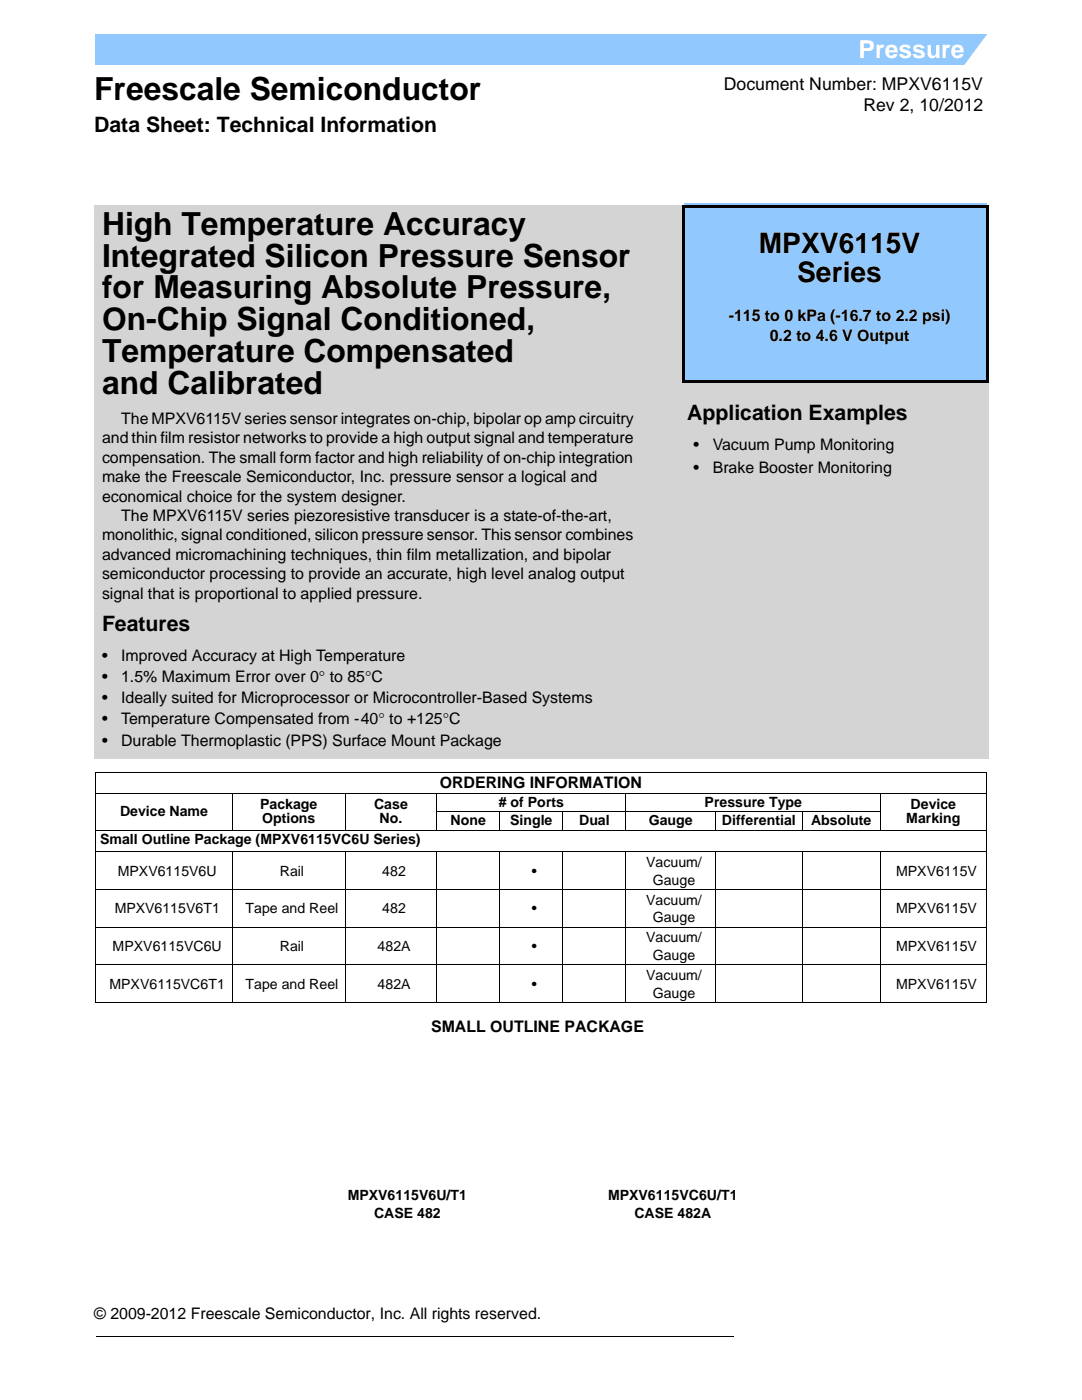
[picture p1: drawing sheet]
<svg xmlns="http://www.w3.org/2000/svg" width="216mm" height="279mm" viewBox="0 0 216 279" stroke-linecap="round" stroke-linejoin="round" font-family="sans-serif">
<defs><g id="words">
<g font-size="6.3">
<text x="18.8" y="19.9">Freescale Semiconductor</text>
<text x="20.4" y="46.8">High Temperature Accuracy</text>
<text x="20.4" y="53.2">Integrated Silicon Pressure Sensor</text>
<text x="20.4" y="59.5">for Measuring Absolute Pressure,</text>
<text x="20.4" y="65.9">On-Chip Signal Conditioned,</text>
<text x="20.4" y="72.2">Temperature Compensated</text>
<text x="20.4" y="78.6">and Calibrated</text>
</g>
<g font-size="5.6">
<text x="151.4" y="50.5">MPXV6115V</text>
<text x="159.1" y="56.3">Series</text>
</g>
<text font-size="4.9" fill="#fff" x="171.3" y="11.7">Pressure</text>
<g font-size="4.2">
<text x="18.8" y="26.3">Data Sheet: Technical Information</text>
<text x="137.1" y="83.9">Application Examples</text>
<text x="20.4" y="125.9">Features</text>
</g>
<g font-size="3.5">
<text x="144.4" y="18">Document Number: MPXV6115V</text>
<text x="172.3" y="22.2">Rev 2, 10/2012</text>
</g>
<g font-size="3.2">
<text x="145.4" y="64.2">-115 to 0 kPa (-16.7 to 2.2 psi)</text>
<text x="153.6" y="68.1">0.2 to 4.6 V Output</text>
<text x="20.4" y="88.5">and thin film resistor networks to provide a high output signal and temperature</text>
<text x="24.2" y="84.6">The MPXV6115V series sensor integrates on-chip, bipolar op amp circuitry</text>
<text x="138.4" y="89.9">•</text>
<text x="142.2" y="89.9">Vacuum Pump Monitoring</text>
<text x="20.4" y="92.4">compensation. The small form factor and high reliability of on-chip integration</text>
<text x="138.4" y="94.5">•</text>
<text x="142.2" y="94.5">Brake Booster Monitoring</text>
<text x="20.4" y="96.2">make the Freescale Semiconductor, Inc. pressure sensor a logical and</text>
<text x="20.4" y="100.1">economical choice for the system designer.</text>
<text x="20.4" y="107.9">monolithic, signal conditioned, silicon pressure sensor. This sensor combines</text>
<text x="24.2" y="104">The MPXV6115V series piezoresistive transducer is a state-of-the-art,</text>
<text x="20.4" y="111.8">advanced micromachining techniques, thin film metallization, and bipolar</text>
<text x="20.4" y="115.6">semiconductor processing to provide an accurate, high level analog output</text>
<text x="20.4" y="119.5">signal that is proportional to applied pressure.</text>
<text x="20.4" y="131.9">•</text>
<text x="24.2" y="131.9">Improved Accuracy at High Temperature</text>
<text x="20.4" y="136.1">•</text>
<text x="24.2" y="136.1">1.5% Maximum Error over 0° to 85°C</text>
<text x="20.4" y="140.3">•</text>
<text x="24.2" y="140.3">Ideally suited for Microprocessor or Microcontroller-Based Systems</text>
<text x="20.4" y="148.8">•</text>
<text x="20.4" y="144.6">•</text>
<text x="24.2" y="148.8">Durable Thermoplastic (PPS) Surface Mount Package</text>
<text x="24.2" y="144.6">Temperature Compensated from -40° to +125°C</text>
<text x="87.8" y="157.3">ORDERING INFORMATION</text>
<text x="86" y="206">SMALL OUTLINE PACKAGE</text>
<text x="18.8" y="263.2">© 2009-2012 Freescale Semiconductor, Inc. All rights reserved.</text>
</g>
<g font-size="2.8">
<text x="51.9" y="161.5">Package</text>
<text x="74.6" y="161.5">Case</text>
<text x="99.5" y="161.1"># of Ports</text>
<text x="140.6" y="161.1">Pressure Type</text>
<text x="181.7" y="161.5">Device</text>
<text x="24" y="162.9">Device Name</text>
<text x="52.3" y="164.3">Options</text>
<text x="75.7" y="164.3">No.</text>
<text x="89.9" y="164.7">None</text>
<text x="101.8" y="164.7">Single</text>
<text x="115.5" y="164.7">Dual</text>
<text x="129.5" y="164.7">Gauge</text>
<text x="144" y="164.7">Differential</text>
<text x="161.8" y="164.7">Absolute</text>
<text x="180.8" y="164.3">Marking</text>
<text x="20" y="168.3">Small Outline Package (MPXV6115VC6U Series)</text>
<text x="128.9" y="173">Vacuum/</text>
<text x="23.5" y="174.8">MPXV6115V6U</text>
<text x="55.8" y="174.8">Rail</text>
<text x="76.3" y="174.8">482</text>
<text x="106.2" y="174.8">•</text>
<text x="130.3" y="176.6">Gauge</text>
<text x="178.8" y="174.8">MPXV6115V</text>
<text x="22.9" y="182.3">MPXV6115V6T1</text>
<text x="49" y="182.3">Tape and Reel</text>
<text x="76.3" y="182.3">482</text>
<text x="106.2" y="182.3">•</text>
<text x="128.9" y="180.6">Vacuum/</text>
<text x="130.3" y="184.1">Gauge</text>
<text x="178.8" y="182.3">MPXV6115V</text>
<text x="22.5" y="189.8">MPXV6115VC6U</text>
<text x="55.8" y="189.8">Rail</text>
<text x="75.4" y="189.8">482A</text>
<text x="106.2" y="189.8">•</text>
<text x="128.9" y="188.1">Vacuum/</text>
<text x="130.3" y="191.6">Gauge</text>
<text x="178.8" y="189.8">MPXV6115V</text>
<text x="21.8" y="197.3">MPXV6115VC6T1</text>
<text x="49" y="197.3">Tape and Reel</text>
<text x="75.4" y="197.3">482A</text>
<text x="106.2" y="197.3">•</text>
<text x="128.9" y="195.6">Vacuum/</text>
<text x="178.8" y="197.3">MPXV6115V</text>
<text x="130.3" y="199.1">Gauge</text>
<text x="69.4" y="239.5">MPXV6115V6U/T1</text>
<text x="121.3" y="239.5">MPXV6115VC6U/T1</text>
<text x="74.6" y="243">CASE 482</text>
<text x="126.6" y="243.1">CASE 482A</text>
</g>
</g></defs>
<path d="M146.3 266.6l.1 .1z" fill="#000"/>
<path d="M19.2 266.6h127.1" fill="none" stroke="#000" stroke-width=".2"/>
<path d="M19 6.9h177.8v6h-177.8z" fill="#91c9ff"/>
<path d="M197.3 6.4h1.5v7.1h-6.8z" fill="#fff"/>
<path d="M152.4 254.6h44v12.8h-44z" fill="#fff"/>
<path d="M134.9 82.9h61.3v41.7h-61.3z" fill="#d4d4d4"/>
<path d="M134.9 82.9h61.3M134.9 82.8v41.8M196.2 82.9v41.8M134.9 124.6h61.3" fill="none" stroke="#d4d4d4" stroke-width=".2"/>
<path d="M18.9 41h178.3v110.3h-178.3z" fill="#d4d4d4"/>
<path d="M18.9 40.9v110.4M18.9 41h178.4M197.2 41v110.4M18.9 151.3h178.3" fill="none" stroke="#d4d4d4" stroke-width=".2"/>
<g fill="#fff">
<path d="M19.1 154.1h177.7v4.3h-177.7z"/>
<path d="M19.1 165.7h177.7v4.3h-177.7z"/>
<path d="M19.1 170h27.3v7.5h-27.3z"/>
<path d="M46.4 170h22.5v7.5h-22.5z"/>
<path d="M68.9 170h18.3v7.5h-18.3z"/>
<path d="M87.2 170h25.1v7.5h-25.1z"/>
<path d="M112.3 170h30.5v7.5h-30.5z"/>
<path d="M142.8 170h54v7.5h-54z"/>
<path d="M19.1 177.5h27.3v7.6h-27.3z"/>
<path d="M46.4 177.5h22.5v7.6h-22.5z"/>
<path d="M68.9 177.5h18.3v7.6h-18.3z"/>
<path d="M87.2 177.5h25.1v7.6h-25.1z"/>
<path d="M112.3 177.5h30.5v7.6h-30.5z"/>
<path d="M142.8 177.5h54v7.6h-54z"/>
<path d="M19.1 185.1h27.3v7.5h-27.3z"/>
<path d="M46.4 185.1h22.5v7.5h-22.5z"/>
<path d="M68.9 185.1h18.3v7.5h-18.3z"/>
<path d="M87.2 185.1h25.1v7.5h-25.1z"/>
<path d="M112.3 185.1h30.5v7.5h-30.5z"/>
<path d="M142.8 185.1h54v7.5h-54z"/>
<path d="M19.1 192.6h27.3v7.5h-27.3z"/>
<path d="M46.4 192.6h22.5v7.5h-22.5z"/>
<path d="M68.9 192.6h18.3v7.5h-18.3z"/>
<path d="M87.2 192.6h25.1v7.5h-25.1z"/>
<path d="M112.3 192.6h30.5v7.5h-30.5z"/>
<path d="M142.8 192.6h54v7.5h-54z"/>
</g>
<g fill="none" stroke="#000" stroke-width=".2">
<path d="M19 154.1h177.9M19 158.4h177.9M19.1 154.2v45.8M46.4 158.3v7.5M68.9 158.3v7.5M87.2 158.3v7.5M124.9 158.3v7.5M175.7 158.3v7.5M196.8 154.2v45.8M19 165.7h177.9M19 170h177.9M19 177.5h177.9"/>
<path d="M46.4 169.9v30.3M68.9 169.9v30.3M87.1 162.1h88.7M87.2 169.9v30.3M99.7 162v3.8M99.7 169.9v30.3M112.3 162v3.8M112.3 169.9v30.3M124.9 169.9v30.3M142.8 162v3.8M142.8 169.9v30.3M160 162v3.8"/>
<path d="M160 169.9v30.3M175.7 169.9v30.3M19 185.1h177.9M19 192.6h177.9M19 200.1h177.9"/>
</g>
<g fill="#fff">
<path d="M68.6 213.4h28v20h-28z"/>
<path d="M120.1 211.5h28.6v23.7h-28.6z"/>
</g>
<path d="M136.6 40.7h60.3v35.1h-60.3z" fill="#91c9ff"/>
<path d="M136.6 40.7h60.4M136.6 40.6v35.2M196.9 40.7v35.2M136.5 75.8h60.4" fill="none" stroke="#91c9ff" stroke-width=".2"/>
<path d="M136.3 40.9h61v.5h-61zM136.1 75.9h60.9v.5h-60.9zM136.1 40.9h.5v35.3h-.5zM196.8 41.1h.5v35.3h-.5z" fill="#000"/>
<use href="#words"/>
</svg>
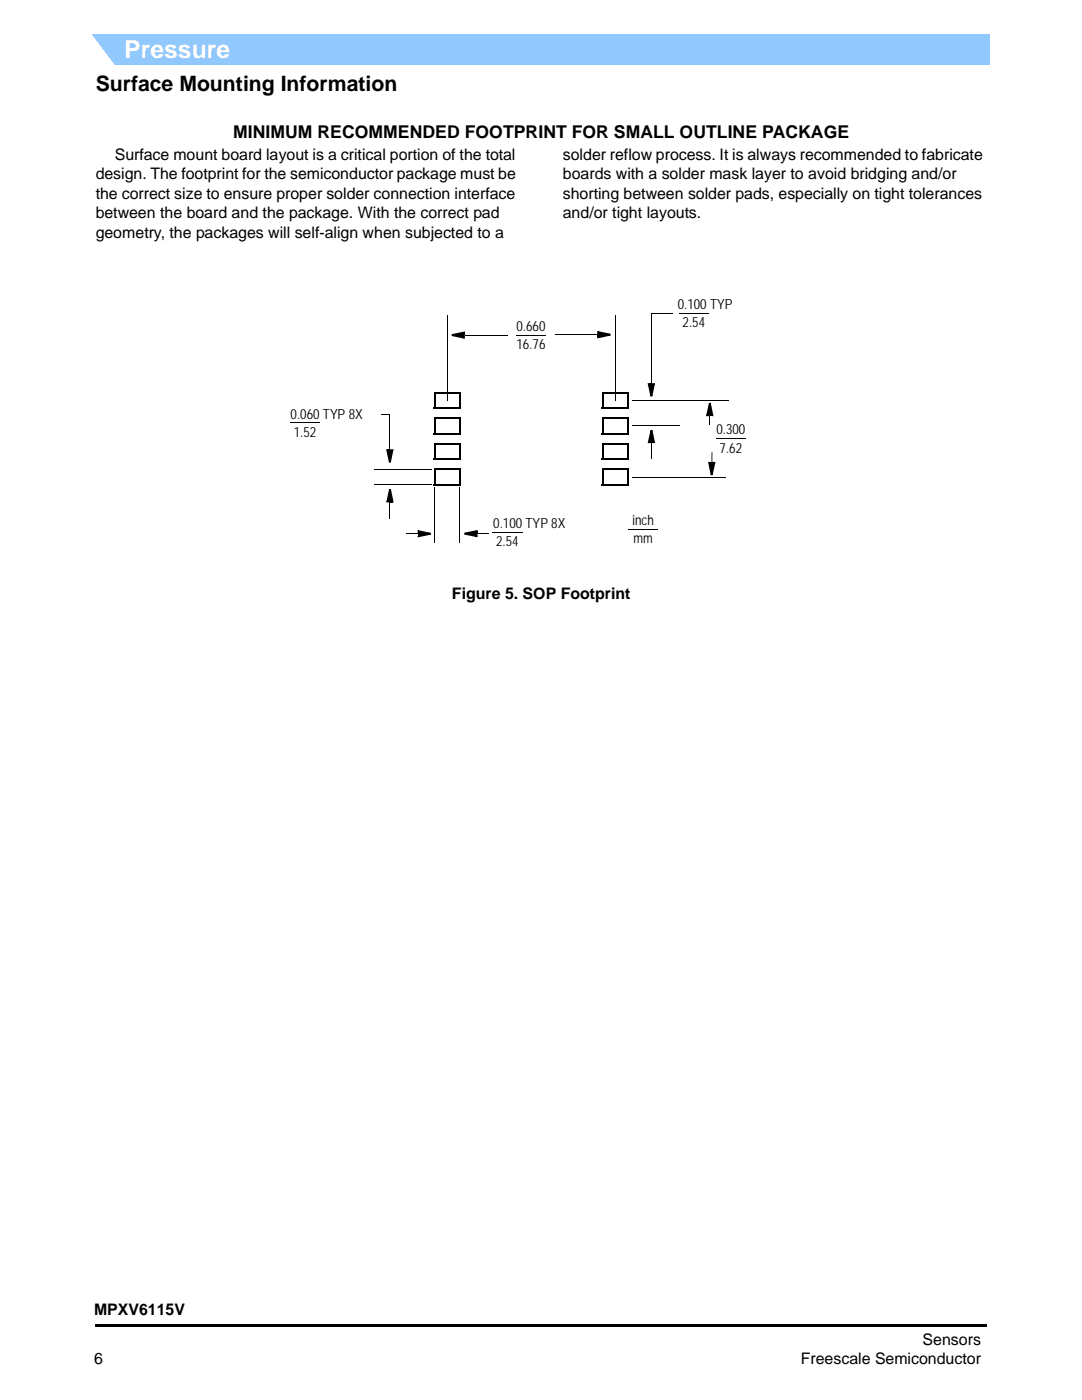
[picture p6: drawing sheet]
<svg xmlns="http://www.w3.org/2000/svg" width="216mm" height="279mm" viewBox="0 0 216 279" stroke-linecap="round" stroke-linejoin="round" font-family="sans-serif">
<defs><g id="words">
<text font-size="4.9" fill="#fff" x="24.8" y="11.7">Pressure</text>
<text font-size="4.2" x="19.1" y="18.2">Surface Mounting Information</text>
<text font-size="3.5" x="46.5" y="27.6">MINIMUM RECOMMENDED FOOTPRINT FOR SMALL OUTLINE PACKAGE</text>
<g font-size="3.2">
<text x="19.1" y="35.8">design. The footprint for the semiconductor package must be</text>
<text x="22.9" y="31.9">Surface mount board layout is a critical portion of the total</text>
<text x="112.3" y="31.9">solder reflow process. It is always recommended to fabricate</text>
<text x="112.3" y="35.8">boards with a solder mask layer to avoid bridging and/or</text>
<text x="19.1" y="39.7">the correct size to ensure proper solder connection interface</text>
<text x="112.3" y="39.7">shorting between solder pads, especially on tight tolerances</text>
<text x="19.1" y="43.6">between the board and the package. With the correct pad</text>
<text x="19.1" y="47.4">geometry, the packages will self-align when subjected to a</text>
<text x="112.3" y="43.6">and/or tight layouts.</text>
<text x="90.2" y="119.5">Figure 5. SOP Footprint</text>
<text x="18.8" y="262.4">MPXV6115V</text>
<text x="184.1" y="268.4">Sensors</text>
<text x="18.8" y="272.3">6</text>
<text x="159.8" y="272.3">Freescale Semiconductor</text>
</g>
<g font-size="2.8">
<text x="135.3" y="61.7">0.100 TYP</text>
<text x="136.2" y="65.3">2.54</text>
<text x="103.1" y="66">0.660</text>
<text x="103.1" y="69.7">16.76</text>
<text x="58" y="83.5">0.060 TYP 8X</text>
<text x="58.6" y="87.1">1.52</text>
<text x="142.9" y="86.7">0.300</text>
<text x="143.6" y="90.3">7.62</text>
<text x="98.4" y="105.4">0.100 TYP 8X</text>
<text x="126.2" y="104.7">inch</text>
<text x="99" y="109.1">2.54</text>
<text x="126.4" y="108.4">mm</text>
</g>
</g></defs>
<path d="M19 264.3h177.7v.6h-177.7zM196.7 264.3h.2v.6h-.2z" fill="#000"/>
<path d="M18.4 6.9h179.2v6h-179.2z" fill="#91c9ff"/>
<path d="M16.5 6.4h1.4l5.4 7.1h-6.8z" fill="#fff"/>
<path d="M21.9 52h172.2v64.7h-172.2z" fill="#fff"/>
<g fill="#000">
<path d="M86.6 78.3h.1v.2h-.1zM89.2 63l.1 .1zM91.7 78.3h.2v.1h-.2zM92.4 66.4h.4v.5h-.4zM90.1 66.7l2.7-.6-.2 .4-2.4 .6v-.4l2.4 .5-.1 .4-.1-.2v-.5h.4v.7l-2.7-.5zM103 66.8l.1 .2zM119.2 66.8h.3v.5h-.3zM119.2 66.1l2.6 .5v.4l-2.6 .5 .1-.4 2.4-.5 .1 .4-2.5-.5 .1-.4 .1 .2v.5h-.3zM120.1 78.3h.1v.2h-.1zM122.7 63l.2 .1zM125.2 78.3h.3v.1h-.3zM129.5 76.5h.5v.3h-.5z"/>
<path d="M129.9 62.5l.1 .2zM129.2 76.5l.4 .1 .6 2.4-.4 .1 .5-2.5 .4 .1-.2 .1h-.5v-.3h.7l-.5 2.6h-.4zM135.5 62.5l.1 .1zM57.8 84.3l.1 .1zM74.6 93.6l.1 .1zM74.6 96.6l.1 .2zM76.1 82.5v.2zM76.1 82.5h1.8v.2h-1.8zM77.3 89.7h.5v.3h-.5zM77 89.7l.4 .1 .6 2.4h-.4l.5-2.4 .4 .1-.2 .1h-.5v-.3h.7l-.5 2.6h-.4zM86.6 93.5h.1v.3h-.1zM86.6 96.7h.2v.1h-.2z"/>
<path d="M86.6 88.4h.1v.3h-.1zM86.6 91.6h.2v.1h-.2zM86.6 83.4h.1v.2h-.1zM86.6 86.5h.2v.2h-.2zM86.6 81.4h.2v.2h-.2zM86.6 97.3l.2 .1zM91.7 93.5h.2v.1h-.2zM91.7 88.4h.2v.2h-.2zM91.7 83.4h.2v.1h-.2zM91.7 97.3l.2 .1zM91.8 96.6h.1v.2h-.1zM91.8 91.5h.1v.3h-.1z"/>
<path d="M91.8 86.4h.1v.3h-.1zM91.8 81.3h.1v.3h-.1zM120.1 93.5h.1v.3h-.1zM120.1 96.7h.3v.1h-.3zM120.1 88.4h.1v.3h-.1zM120.1 91.6h.3v.1h-.3zM120.1 83.4h.1v.2h-.1zM120.1 86.5h.3v.2h-.3zM120.1 81.4h.3v.2h-.3zM125.2 93.5h.3v.1h-.3zM125.2 88.4h.3v.2h-.3zM125.2 83.4h.3v.1h-.3z"/>
<path d="M125.3 96.6h.1v.2h-.1zM125.3 91.5h.1v.3h-.1zM125.3 86.4h.1v.3h-.1zM125.3 81.3h.1v.3h-.1zM126.1 79.8l.1 .2zM126.1 84.9l.1 .2zM126.1 95.1l.1 .2zM129.8 85.8h.4l.5 2.6-.4-.1-.5-2.4h.4l-.6 2.4-.3-.1 .2-.1h.5v.3h-.8zM130 88.1h.5v.3h-.5zM141.5 92.2h.5v.3h-.5zM141.5 83.1h.2v1.7h-.2zM141.5 80.4h.3l.6 2.7-.4-.2-.5-2.4h.3l-.5 2.4-.4-.1 .2-.1h.5v.4h-.7z"/>
<path d="M141.6 82.7h.5v.4h-.5zM141.3 92.2l.4 .1 .5 2.4-.4 .1 .6-2.5 .3 .1-.1 .1h-.6v-.3h.8l-.6 2.6h-.4zM142 90.3h.2l-.1 1.9h-.1zM142.8 87.5l.1 .1zM77.6 97.6h.4l.5 2.7-.4-.2-.5-2.4h.4l-.5 2.4h-.4l.2-.2h.5v.4h-.7zM77.8 99.9h.5v.4h-.5zM83.3 105.8l2.7 .5v.4l-2.7 .6 .2-.5 2.4-.5v.4l-2.4-.5v-.4l.2 .2v.5h-.4zM83.3 106.5h.4v.5h-.4zM94.9 106h.4v.5h-.4zM92.7 106.3l2.6-.5-.1 .4-2.4 .5v-.4l2.4 .5-.1 .4-.2-.2v-.5h.4v.7l-2.6-.5zM98.2 106.2l.1 .2zM125.3 105.5l.1 .2z"/>
</g>
<g fill="none" stroke="#000" stroke-width=".28">
<path d="M86.7 78.4h5.2M86.7 78.3v3.1M91.8 78.4v3.2M120.2 78.4h5.2M120.2 78.3v3.1M125.3 78.4v3.2M86.6 96.7h5.2M86.6 91.6h5.2M86.6 86.5h5.2M86.6 81.5h5.2M86.7 93.7h5.2M86.7 88.6h5.2"/>
<path d="M86.7 83.5h5.2M86.7 83.4v3.1M86.7 88.4v3.2M86.7 93.5v3.2M91.8 83.5v3.2M91.8 88.6v3.1M91.8 93.6v3.2M120.1 96.7h5.2M120.1 91.6h5.2M120.1 86.5h5.2M120.1 81.5h5.2M120.2 93.7h5.2"/>
<path d="M120.2 88.6h5.2M120.2 83.5h5.2M120.2 83.4v3.1M120.2 88.4v3.2M120.2 93.5v3.2M125.3 83.5v3.2M125.3 88.6v3.1M125.3 93.6v3.2"/>
</g>
<g fill="none" stroke="#000" stroke-width=".2">
<path d="M89.2 63.1v16.8M92.8 66.9h8.5M103.1 66.9h5.9M110.7 66.8h8.5M122.8 63.1v16.8M126.2 79.9h19.3M134.3 62.6h-4.3v13.9M135.6 62.5h5.9M57.9 84.3h5.9M74.7 93.6h11.4M74.7 96.7h11.4M77.8 82.6v7.1"/>
<path d="M86.7 97.4v10.8M91.8 97.4v10.8M126.2 85h9.5M126.2 95.2h18.5M130 88.5v3M142.9 87.5h5.9M77.8 100.3v3.3M80.9 106.5h2.4M95.3 106.5h2.2M98.3 106.3h6M125.4 105.6h6"/>
</g>
<path d="M90.2 66.9l2.4-.5v1zM119.3 66.3l2.5 .5-2.5 .5zM129.5 76.6h1l-.5 2.5zM77.3 89.8h1l-.5 2.5zM130 85.9l.5 2.4h-1zM141.6 80.5l.5 2.4h-1zM141.5 92.4h1.1l-.6 2.4zM77.8 97.7l.5 2.4h-1zM83.5 106l2.4 .5-2.4 .5zM92.7 106.5l2.4-.5v1z" fill="#000"/>
<use href="#words"/>
</svg>
